VERSION 5.7 ;
BUSBITCHARS "[]" ;
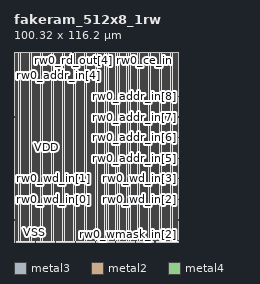
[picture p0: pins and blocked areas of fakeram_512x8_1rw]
MACRO fakeram_512x8_1rw
  FOREIGN fakeram_512x8_1rw 0 0 ;
  SYMMETRY X Y R90 ;
  SIZE 100.320 BY 116.200 ;
  CLASS BLOCK ;
  PIN rw0_wmask_in[0]
    DIRECTION INPUT ;
    USE SIGNAL ;
    SHAPE ABUTMENT ;
    PORT
      LAYER metal3 ;
      RECT 0.000 0.805 0.210 0.875 ;
    END
  END rw0_wmask_in[0]
  PIN rw0_wmask_in[1]
    DIRECTION INPUT ;
    USE SIGNAL ;
    SHAPE ABUTMENT ;
    PORT
      LAYER metal3 ;
      RECT 0.000 13.405 0.210 13.475 ;
    END
  END rw0_wmask_in[1]
  PIN rw0_wmask_in[2]
    DIRECTION INPUT ;
    USE SIGNAL ;
    SHAPE ABUTMENT ;
    PORT
      LAYER metal3 ;
      RECT 100.110 0.805 100.320 0.875 ;
    END
  END rw0_wmask_in[2]
  PIN rw0_wmask_in[3]
    DIRECTION INPUT ;
    USE SIGNAL ;
    SHAPE ABUTMENT ;
    PORT
      LAYER metal3 ;
      RECT 100.110 13.405 100.320 13.475 ;
    END
  END rw0_wmask_in[3]
  PIN rw0_wmask_in[4]
    DIRECTION INPUT ;
    USE SIGNAL ;
    SHAPE ABUTMENT ;
    PORT
      LAYER metal2 ;
      RECT 1.105 115.990 1.175 116.200 ;
    END
  END rw0_wmask_in[4]
  PIN rw0_wmask_in[5]
    DIRECTION INPUT ;
    USE SIGNAL ;
    SHAPE ABUTMENT ;
    PORT
      LAYER metal2 ;
      RECT 9.845 115.990 9.915 116.200 ;
    END
  END rw0_wmask_in[5]
  PIN rw0_wmask_in[6]
    DIRECTION INPUT ;
    USE SIGNAL ;
    SHAPE ABUTMENT ;
    PORT
      LAYER metal2 ;
      RECT 18.585 115.990 18.655 116.200 ;
    END
  END rw0_wmask_in[6]
  PIN rw0_wmask_in[7]
    DIRECTION INPUT ;
    USE SIGNAL ;
    SHAPE ABUTMENT ;
    PORT
      LAYER metal2 ;
      RECT 27.325 115.990 27.395 116.200 ;
    END
  END rw0_wmask_in[7]
  PIN rw0_wd_in[0]
    DIRECTION INPUT ;
    USE SIGNAL ;
    SHAPE ABUTMENT ;
    PORT
      LAYER metal3 ;
      RECT 0.000 26.005 0.210 26.075 ;
    END
  END rw0_wd_in[0]
  PIN rw0_wd_in[1]
    DIRECTION INPUT ;
    USE SIGNAL ;
    SHAPE ABUTMENT ;
    PORT
      LAYER metal3 ;
      RECT 0.000 38.605 0.210 38.675 ;
    END
  END rw0_wd_in[1]
  PIN rw0_wd_in[2]
    DIRECTION INPUT ;
    USE SIGNAL ;
    SHAPE ABUTMENT ;
    PORT
      LAYER metal3 ;
      RECT 100.110 26.005 100.320 26.075 ;
    END
  END rw0_wd_in[2]
  PIN rw0_wd_in[3]
    DIRECTION INPUT ;
    USE SIGNAL ;
    SHAPE ABUTMENT ;
    PORT
      LAYER metal3 ;
      RECT 100.110 38.605 100.320 38.675 ;
    END
  END rw0_wd_in[3]
  PIN rw0_wd_in[4]
    DIRECTION INPUT ;
    USE SIGNAL ;
    SHAPE ABUTMENT ;
    PORT
      LAYER metal2 ;
      RECT 1.105 0.000 1.175 0.210 ;
    END
  END rw0_wd_in[4]
  PIN rw0_wd_in[5]
    DIRECTION INPUT ;
    USE SIGNAL ;
    SHAPE ABUTMENT ;
    PORT
      LAYER metal2 ;
      RECT 13.265 0.000 13.335 0.210 ;
    END
  END rw0_wd_in[5]
  PIN rw0_wd_in[6]
    DIRECTION INPUT ;
    USE SIGNAL ;
    SHAPE ABUTMENT ;
    PORT
      LAYER metal2 ;
      RECT 25.425 0.000 25.495 0.210 ;
    END
  END rw0_wd_in[6]
  PIN rw0_wd_in[7]
    DIRECTION INPUT ;
    USE SIGNAL ;
    SHAPE ABUTMENT ;
    PORT
      LAYER metal2 ;
      RECT 37.585 0.000 37.655 0.210 ;
    END
  END rw0_wd_in[7]
  PIN rw0_rd_out[0]
    DIRECTION OUTPUT ;
    USE SIGNAL ;
    SHAPE ABUTMENT ;
    PORT
      LAYER metal2 ;
      RECT 49.745 0.000 49.815 0.210 ;
    END
  END rw0_rd_out[0]
  PIN rw0_rd_out[1]
    DIRECTION OUTPUT ;
    USE SIGNAL ;
    SHAPE ABUTMENT ;
    PORT
      LAYER metal2 ;
      RECT 61.905 0.000 61.975 0.210 ;
    END
  END rw0_rd_out[1]
  PIN rw0_rd_out[2]
    DIRECTION OUTPUT ;
    USE SIGNAL ;
    SHAPE ABUTMENT ;
    PORT
      LAYER metal2 ;
      RECT 74.065 0.000 74.135 0.210 ;
    END
  END rw0_rd_out[2]
  PIN rw0_rd_out[3]
    DIRECTION OUTPUT ;
    USE SIGNAL ;
    SHAPE ABUTMENT ;
    PORT
      LAYER metal2 ;
      RECT 86.225 0.000 86.295 0.210 ;
    END
  END rw0_rd_out[3]
  PIN rw0_rd_out[4]
    DIRECTION OUTPUT ;
    USE SIGNAL ;
    SHAPE ABUTMENT ;
    PORT
      LAYER metal2 ;
      RECT 36.065 115.990 36.135 116.200 ;
    END
  END rw0_rd_out[4]
  PIN rw0_rd_out[5]
    DIRECTION OUTPUT ;
    USE SIGNAL ;
    SHAPE ABUTMENT ;
    PORT
      LAYER metal2 ;
      RECT 44.805 115.990 44.875 116.200 ;
    END
  END rw0_rd_out[5]
  PIN rw0_rd_out[6]
    DIRECTION OUTPUT ;
    USE SIGNAL ;
    SHAPE ABUTMENT ;
    PORT
      LAYER metal2 ;
      RECT 53.545 115.990 53.615 116.200 ;
    END
  END rw0_rd_out[6]
  PIN rw0_rd_out[7]
    DIRECTION OUTPUT ;
    USE SIGNAL ;
    SHAPE ABUTMENT ;
    PORT
      LAYER metal2 ;
      RECT 62.285 115.990 62.355 116.200 ;
    END
  END rw0_rd_out[7]
  PIN rw0_addr_in[0]
    DIRECTION INPUT ;
    USE SIGNAL ;
    SHAPE ABUTMENT ;
    PORT
      LAYER metal3 ;
      RECT 0.000 51.205 0.210 51.275 ;
    END
  END rw0_addr_in[0]
  PIN rw0_addr_in[1]
    DIRECTION INPUT ;
    USE SIGNAL ;
    SHAPE ABUTMENT ;
    PORT
      LAYER metal3 ;
      RECT 0.000 63.805 0.210 63.875 ;
    END
  END rw0_addr_in[1]
  PIN rw0_addr_in[2]
    DIRECTION INPUT ;
    USE SIGNAL ;
    SHAPE ABUTMENT ;
    PORT
      LAYER metal3 ;
      RECT 0.000 76.405 0.210 76.475 ;
    END
  END rw0_addr_in[2]
  PIN rw0_addr_in[3]
    DIRECTION INPUT ;
    USE SIGNAL ;
    SHAPE ABUTMENT ;
    PORT
      LAYER metal3 ;
      RECT 0.000 89.005 0.210 89.075 ;
    END
  END rw0_addr_in[3]
  PIN rw0_addr_in[4]
    DIRECTION INPUT ;
    USE SIGNAL ;
    SHAPE ABUTMENT ;
    PORT
      LAYER metal3 ;
      RECT 0.000 101.605 0.210 101.675 ;
    END
  END rw0_addr_in[4]
  PIN rw0_addr_in[5]
    DIRECTION INPUT ;
    USE SIGNAL ;
    SHAPE ABUTMENT ;
    PORT
      LAYER metal3 ;
      RECT 100.110 51.205 100.320 51.275 ;
    END
  END rw0_addr_in[5]
  PIN rw0_addr_in[6]
    DIRECTION INPUT ;
    USE SIGNAL ;
    SHAPE ABUTMENT ;
    PORT
      LAYER metal3 ;
      RECT 100.110 63.805 100.320 63.875 ;
    END
  END rw0_addr_in[6]
  PIN rw0_addr_in[7]
    DIRECTION INPUT ;
    USE SIGNAL ;
    SHAPE ABUTMENT ;
    PORT
      LAYER metal3 ;
      RECT 100.110 76.405 100.320 76.475 ;
    END
  END rw0_addr_in[7]
  PIN rw0_addr_in[8]
    DIRECTION INPUT ;
    USE SIGNAL ;
    SHAPE ABUTMENT ;
    PORT
      LAYER metal3 ;
      RECT 100.110 89.005 100.320 89.075 ;
    END
  END rw0_addr_in[8]
  PIN rw0_we_in
    DIRECTION INPUT ;
    USE SIGNAL ;
    SHAPE ABUTMENT ;
    PORT
      LAYER metal2 ;
      RECT 71.025 115.990 71.095 116.200 ;
    END
  END rw0_we_in
  PIN rw0_ce_in
    DIRECTION INPUT ;
    USE SIGNAL ;
    SHAPE ABUTMENT ;
    PORT
      LAYER metal2 ;
      RECT 79.765 115.990 79.835 116.200 ;
    END
  END rw0_ce_in
  PIN rw0_clk
    DIRECTION INPUT ;
    USE SIGNAL ;
    SHAPE ABUTMENT ;
    PORT
      LAYER metal2 ;
      RECT 88.505 115.990 88.575 116.200 ;
    END
  END rw0_clk
  PIN VSS
    DIRECTION INOUT ;
    USE GROUND ;
    PORT
      LAYER metal4 ;
      RECT 1.000 0.840 1.280 115.360 ;
      RECT 3.240 0.840 3.520 115.360 ;
      RECT 5.480 0.840 5.760 115.360 ;
      RECT 7.720 0.840 8.000 115.360 ;
      RECT 9.960 0.840 10.240 115.360 ;
      RECT 12.200 0.840 12.480 115.360 ;
      RECT 14.440 0.840 14.720 115.360 ;
      RECT 16.680 0.840 16.960 115.360 ;
      RECT 18.920 0.840 19.200 115.360 ;
      RECT 21.160 0.840 21.440 115.360 ;
      RECT 23.400 0.840 23.680 115.360 ;
      RECT 25.640 0.840 25.920 115.360 ;
      RECT 27.880 0.840 28.160 115.360 ;
      RECT 30.120 0.840 30.400 115.360 ;
      RECT 32.360 0.840 32.640 115.360 ;
      RECT 34.600 0.840 34.880 115.360 ;
      RECT 36.840 0.840 37.120 115.360 ;
      RECT 39.080 0.840 39.360 115.360 ;
      RECT 41.320 0.840 41.600 115.360 ;
      RECT 43.560 0.840 43.840 115.360 ;
      RECT 45.800 0.840 46.080 115.360 ;
      RECT 48.040 0.840 48.320 115.360 ;
      RECT 50.280 0.840 50.560 115.360 ;
      RECT 52.520 0.840 52.800 115.360 ;
      RECT 54.760 0.840 55.040 115.360 ;
      RECT 57.000 0.840 57.280 115.360 ;
      RECT 59.240 0.840 59.520 115.360 ;
      RECT 61.480 0.840 61.760 115.360 ;
      RECT 63.720 0.840 64.000 115.360 ;
      RECT 65.960 0.840 66.240 115.360 ;
      RECT 68.200 0.840 68.480 115.360 ;
      RECT 70.440 0.840 70.720 115.360 ;
      RECT 72.680 0.840 72.960 115.360 ;
      RECT 74.920 0.840 75.200 115.360 ;
      RECT 77.160 0.840 77.440 115.360 ;
      RECT 79.400 0.840 79.680 115.360 ;
      RECT 81.640 0.840 81.920 115.360 ;
      RECT 83.880 0.840 84.160 115.360 ;
      RECT 86.120 0.840 86.400 115.360 ;
      RECT 88.360 0.840 88.640 115.360 ;
      RECT 90.600 0.840 90.880 115.360 ;
      RECT 92.840 0.840 93.120 115.360 ;
      RECT 95.080 0.840 95.360 115.360 ;
      RECT 97.320 0.840 97.600 115.360 ;
      RECT 99.560 0.840 99.840 115.360 ;
    END
  END VSS
  PIN VDD
    DIRECTION INOUT ;
    USE POWER ;
    PORT
      LAYER metal4 ;
      RECT 2.120 0.840 2.400 115.360 ;
      RECT 4.360 0.840 4.640 115.360 ;
      RECT 6.600 0.840 6.880 115.360 ;
      RECT 8.840 0.840 9.120 115.360 ;
      RECT 11.080 0.840 11.360 115.360 ;
      RECT 13.320 0.840 13.600 115.360 ;
      RECT 15.560 0.840 15.840 115.360 ;
      RECT 17.800 0.840 18.080 115.360 ;
      RECT 20.040 0.840 20.320 115.360 ;
      RECT 22.280 0.840 22.560 115.360 ;
      RECT 24.520 0.840 24.800 115.360 ;
      RECT 26.760 0.840 27.040 115.360 ;
      RECT 29.000 0.840 29.280 115.360 ;
      RECT 31.240 0.840 31.520 115.360 ;
      RECT 33.480 0.840 33.760 115.360 ;
      RECT 35.720 0.840 36.000 115.360 ;
      RECT 37.960 0.840 38.240 115.360 ;
      RECT 40.200 0.840 40.480 115.360 ;
      RECT 42.440 0.840 42.720 115.360 ;
      RECT 44.680 0.840 44.960 115.360 ;
      RECT 46.920 0.840 47.200 115.360 ;
      RECT 49.160 0.840 49.440 115.360 ;
      RECT 51.400 0.840 51.680 115.360 ;
      RECT 53.640 0.840 53.920 115.360 ;
      RECT 55.880 0.840 56.160 115.360 ;
      RECT 58.120 0.840 58.400 115.360 ;
      RECT 60.360 0.840 60.640 115.360 ;
      RECT 62.600 0.840 62.880 115.360 ;
      RECT 64.840 0.840 65.120 115.360 ;
      RECT 67.080 0.840 67.360 115.360 ;
      RECT 69.320 0.840 69.600 115.360 ;
      RECT 71.560 0.840 71.840 115.360 ;
      RECT 73.800 0.840 74.080 115.360 ;
      RECT 76.040 0.840 76.320 115.360 ;
      RECT 78.280 0.840 78.560 115.360 ;
      RECT 80.520 0.840 80.800 115.360 ;
      RECT 82.760 0.840 83.040 115.360 ;
      RECT 85.000 0.840 85.280 115.360 ;
      RECT 87.240 0.840 87.520 115.360 ;
      RECT 89.480 0.840 89.760 115.360 ;
      RECT 91.720 0.840 92.000 115.360 ;
      RECT 93.960 0.840 94.240 115.360 ;
      RECT 96.200 0.840 96.480 115.360 ;
      RECT 98.440 0.840 98.720 115.360 ;
    END
  END VDD
  OBS
    LAYER metal1 ;
    RECT 0 0 100.320 116.200 ;
    LAYER metal2 ;
    RECT 0 0 100.320 116.200 ;
    LAYER metal3 ;
    RECT 0 0 100.320 116.200 ;
    LAYER metal4 ;
    RECT 0 0 100.320 116.200 ;
    LAYER OVERLAP ;
    RECT 0 0 100.320 116.200 ;
  END
END fakeram_512x8_1rw

END LIBRARY
